VERSION 5.7 ;
  NOWIREEXTENSIONATPIN ON ;
  DIVIDERCHAR "/" ;
  BUSBITCHARS "[]" ;
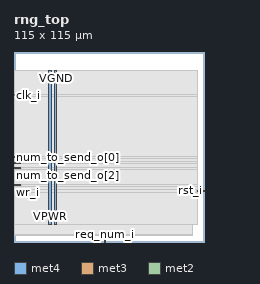
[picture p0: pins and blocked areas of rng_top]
MACRO rng_top
  CLASS BLOCK ;
  FOREIGN rng_top ;
  ORIGIN 0.000 0.000 ;
  SIZE 115.000 BY 115.000 ;
  PIN VGND
    DIRECTION INOUT ;
    USE GROUND ;
    PORT
      LAYER met4 ;
        RECT 24.340 10.640 25.940 103.600 ;
    END
  END VGND
  PIN VPWR
    DIRECTION INOUT ;
    USE POWER ;
    PORT
      LAYER met4 ;
        RECT 21.040 10.640 22.640 103.600 ;
    END
  END VPWR
  PIN clk_i
    DIRECTION INPUT ;
    USE SIGNAL ;
    ANTENNAGATEAREA 0.852000 ;
    PORT
      LAYER met3 ;
        RECT 0.000 88.440 4.000 89.040 ;
    END
  END clk_i
  PIN num_to_send_o[0]
    DIRECTION OUTPUT ;
    USE SIGNAL ;
    ANTENNADIFFAREA 0.445500 ;
    PORT
      LAYER met3 ;
        RECT 0.000 51.040 4.000 51.640 ;
    END
  END num_to_send_o[0]
  PIN num_to_send_o[1]
    DIRECTION OUTPUT ;
    USE SIGNAL ;
    ANTENNADIFFAREA 0.445500 ;
    PORT
      LAYER met3 ;
        RECT 0.000 47.640 4.000 48.240 ;
    END
  END num_to_send_o[1]
  PIN num_to_send_o[2]
    DIRECTION OUTPUT ;
    USE SIGNAL ;
    ANTENNADIFFAREA 0.445500 ;
    PORT
      LAYER met3 ;
        RECT 0.000 44.240 4.000 44.840 ;
    END
  END num_to_send_o[2]
  PIN req_num_i
    DIRECTION INPUT ;
    USE SIGNAL ;
    ANTENNAGATEAREA 0.196500 ;
    PORT
      LAYER met2 ;
        RECT 54.830 0.000 55.110 4.000 ;
    END
  END req_num_i
  PIN rst_i
    DIRECTION INPUT ;
    USE SIGNAL ;
    ANTENNAGATEAREA 0.196500 ;
    PORT
      LAYER met3 ;
        RECT 111.000 30.640 115.000 31.240 ;
    END
  END rst_i
  PIN wr_i
    DIRECTION INPUT ;
    USE SIGNAL ;
    ANTENNAGATEAREA 0.196500 ;
    PORT
      LAYER met3 ;
        RECT 0.000 34.040 4.000 34.640 ;
    END
  END wr_i
  OBS
      LAYER nwell ;
        RECT 5.330 10.760 109.670 103.445 ;
      LAYER li1 ;
        RECT 5.520 10.795 109.480 103.445 ;
      LAYER met1 ;
        RECT 0.530 10.640 109.480 103.600 ;
      LAYER met2 ;
        RECT 0.550 4.280 108.010 103.545 ;
        RECT 0.550 4.000 54.550 4.280 ;
        RECT 55.390 4.000 108.010 4.280 ;
      LAYER met3 ;
        RECT 0.525 89.440 111.000 103.525 ;
        RECT 4.400 88.040 111.000 89.440 ;
        RECT 0.525 52.040 111.000 88.040 ;
        RECT 4.400 50.640 111.000 52.040 ;
        RECT 0.525 48.640 111.000 50.640 ;
        RECT 4.400 47.240 111.000 48.640 ;
        RECT 0.525 45.240 111.000 47.240 ;
        RECT 4.400 43.840 111.000 45.240 ;
        RECT 0.525 35.040 111.000 43.840 ;
        RECT 4.400 33.640 111.000 35.040 ;
        RECT 0.525 31.640 111.000 33.640 ;
        RECT 0.525 30.240 110.600 31.640 ;
        RECT 0.525 10.715 111.000 30.240 ;
  END
END rng_top
END LIBRARY

